VERSION 5.7 ;
  NOWIREEXTENSIONATPIN ON ;
  DIVIDERCHAR "/" ;
  BUSBITCHARS "[]" ;
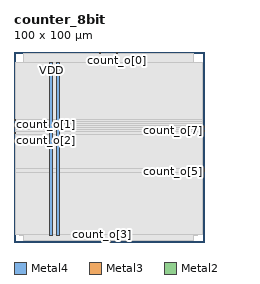
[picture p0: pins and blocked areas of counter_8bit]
MACRO counter_8bit
  CLASS BLOCK ;
  FOREIGN counter_8bit ;
  ORIGIN 0.000 0.000 ;
  SIZE 100.000 BY 100.000 ;
  PIN VDD
    DIRECTION INOUT ;
    USE POWER ;
    PORT
      LAYER Metal4 ;
        RECT 18.880 3.620 20.480 94.380 ;
    END
  END VDD
  PIN VSS
    DIRECTION INOUT ;
    USE GROUND ;
    PORT
      LAYER Metal4 ;
        RECT 22.180 3.620 23.780 94.380 ;
    END
  END VSS
  PIN clk_i
    DIRECTION INPUT ;
    USE SIGNAL ;
    ANTENNAGATEAREA 4.738000 ;
    PORT
      LAYER Metal3 ;
        RECT 0.000 63.840 0.560 64.400 ;
    END
  END clk_i
  PIN count_o[0]
    DIRECTION OUTPUT ;
    USE SIGNAL ;
    ANTENNADIFFAREA 0.897600 ;
    PORT
      LAYER Metal2 ;
        RECT 53.760 99.440 54.320 100.000 ;
    END
  END count_o[0]
  PIN count_o[1]
    DIRECTION OUTPUT ;
    USE SIGNAL ;
    ANTENNADIFFAREA 0.897600 ;
    PORT
      LAYER Metal3 ;
        RECT 0.000 61.600 0.560 62.160 ;
    END
  END count_o[1]
  PIN count_o[2]
    DIRECTION OUTPUT ;
    USE SIGNAL ;
    ANTENNADIFFAREA 0.897600 ;
    PORT
      LAYER Metal3 ;
        RECT 0.000 57.120 0.560 57.680 ;
    END
  END count_o[2]
  PIN count_o[3]
    DIRECTION OUTPUT ;
    USE SIGNAL ;
    ANTENNADIFFAREA 0.897600 ;
    PORT
      LAYER Metal2 ;
        RECT 45.920 0.000 46.480 0.560 ;
    END
  END count_o[3]
  PIN count_o[4]
    DIRECTION OUTPUT ;
    USE SIGNAL ;
    ANTENNADIFFAREA 0.897600 ;
    PORT
      LAYER Metal2 ;
        RECT 50.400 0.000 50.960 0.560 ;
    END
  END count_o[4]
  PIN count_o[5]
    DIRECTION OUTPUT ;
    USE SIGNAL ;
    ANTENNADIFFAREA 0.897600 ;
    PORT
      LAYER Metal3 ;
        RECT 99.440 36.960 100.000 37.520 ;
    END
  END count_o[5]
  PIN count_o[6]
    DIRECTION OUTPUT ;
    USE SIGNAL ;
    ANTENNADIFFAREA 0.897600 ;
    PORT
      LAYER Metal3 ;
        RECT 99.440 38.080 100.000 38.640 ;
    END
  END count_o[6]
  PIN count_o[7]
    DIRECTION OUTPUT ;
    USE SIGNAL ;
    ANTENNADIFFAREA 0.897600 ;
    PORT
      LAYER Metal3 ;
        RECT 99.440 58.240 100.000 58.800 ;
    END
  END count_o[7]
  PIN en_i
    DIRECTION INPUT ;
    USE SIGNAL ;
    ANTENNAGATEAREA 0.396000 ;
    PORT
      LAYER Metal2 ;
        RECT 44.800 99.440 45.360 100.000 ;
    END
  END en_i
  PIN ovf_o
    DIRECTION OUTPUT ;
    USE SIGNAL ;
    ANTENNADIFFAREA 0.897600 ;
    PORT
      LAYER Metal3 ;
        RECT 99.440 60.480 100.000 61.040 ;
    END
  END ovf_o
  PIN rst_ni
    DIRECTION INPUT ;
    USE SIGNAL ;
    ANTENNAGATEAREA 0.396000 ;
    PORT
      LAYER Metal3 ;
        RECT 0.000 60.480 0.560 61.040 ;
    END
  END rst_ni
  OBS
      LAYER Nwell ;
        RECT 2.930 3.490 96.750 94.510 ;
      LAYER Metal1 ;
        RECT 3.360 3.620 96.320 94.380 ;
      LAYER Metal2 ;
        RECT 5.180 99.140 44.500 99.440 ;
        RECT 45.660 99.140 53.460 99.440 ;
        RECT 54.620 99.140 94.500 99.440 ;
        RECT 5.180 0.860 94.500 99.140 ;
        RECT 5.180 0.560 45.620 0.860 ;
        RECT 46.780 0.560 50.100 0.860 ;
        RECT 51.260 0.560 94.500 0.860 ;
      LAYER Metal3 ;
        RECT 0.560 64.700 99.440 94.220 ;
        RECT 0.860 63.540 99.440 64.700 ;
        RECT 0.560 62.460 99.440 63.540 ;
        RECT 0.860 61.340 99.440 62.460 ;
        RECT 0.860 60.180 99.140 61.340 ;
        RECT 0.560 59.100 99.440 60.180 ;
        RECT 0.560 57.980 99.140 59.100 ;
        RECT 0.860 57.940 99.140 57.980 ;
        RECT 0.860 56.820 99.440 57.940 ;
        RECT 0.560 38.940 99.440 56.820 ;
        RECT 0.560 36.660 99.140 38.940 ;
        RECT 0.560 3.780 99.440 36.660 ;
  END
END counter_8bit
END LIBRARY

